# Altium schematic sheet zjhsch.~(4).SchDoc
size A4

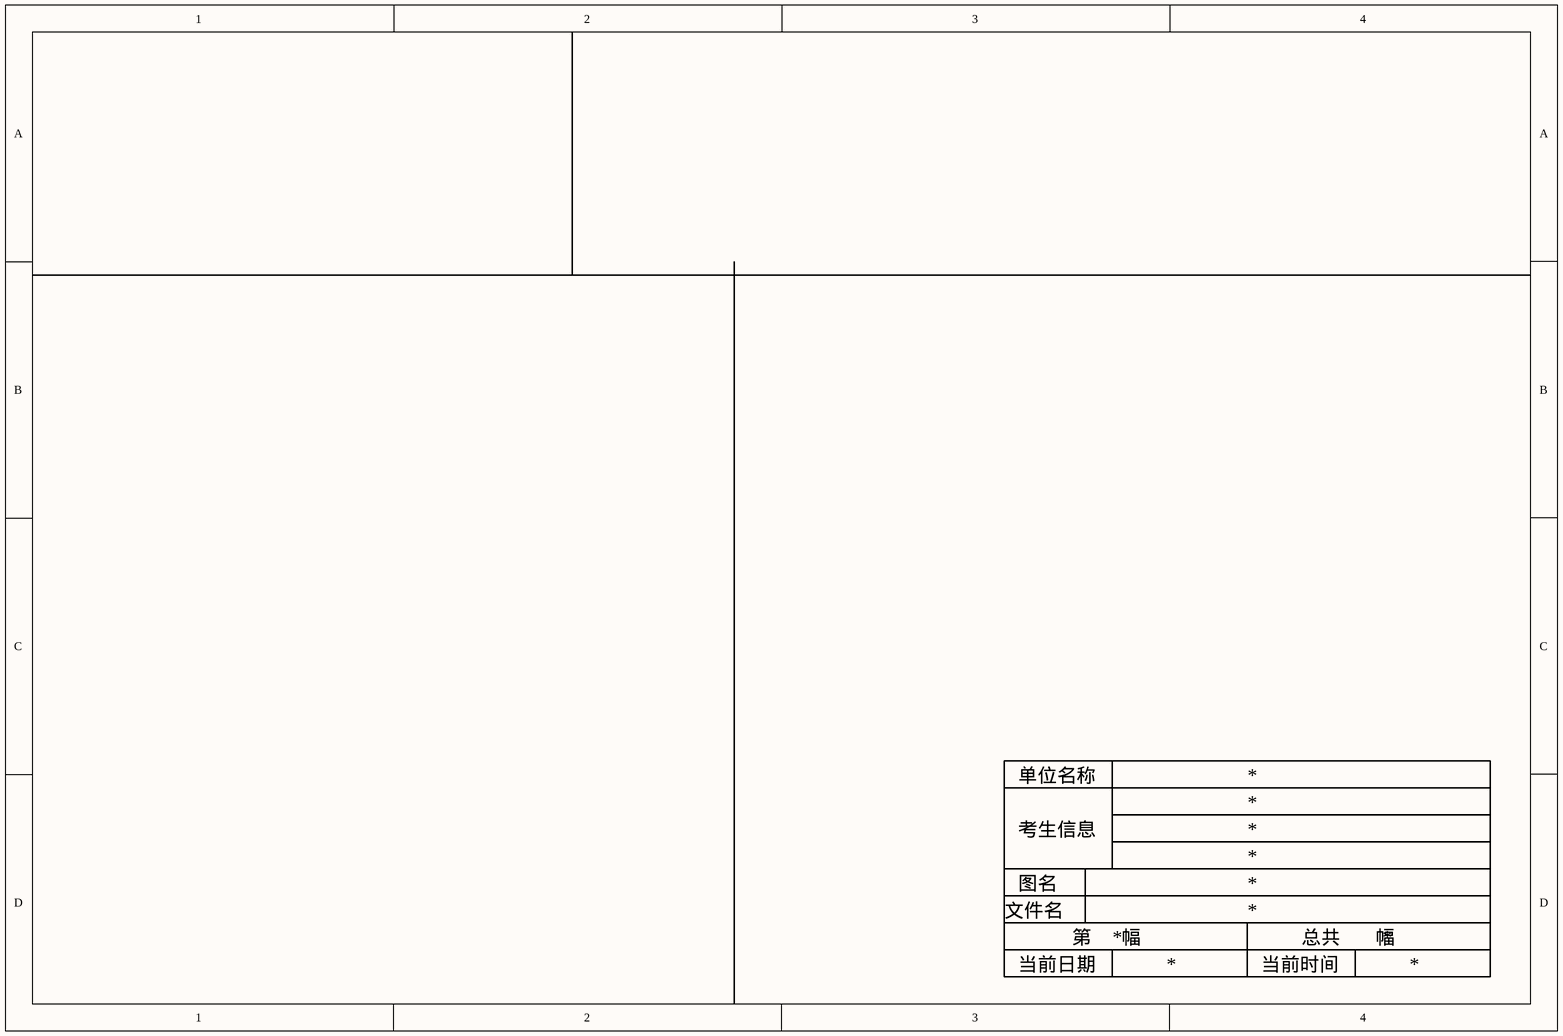
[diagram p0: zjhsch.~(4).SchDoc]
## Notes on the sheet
- 单位名称
- 考生信息
- 文件名
- 图名
- 当前日期
- 第      幅
- 当前时间
- 总共       幅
